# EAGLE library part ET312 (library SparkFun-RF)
ET312 GPS Receiver Proven layout and schematic for SiRF III ET312 GPS receiver. This footprint has been tweaked significantly to work with the ET312. This footprint has been fully qualified. Spark Fun Electronics SKU : GPS-08268.

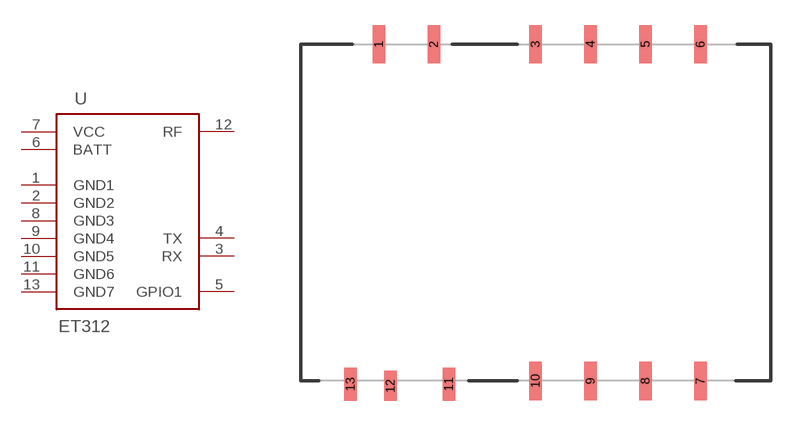
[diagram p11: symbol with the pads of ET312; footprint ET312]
Designator prefix -

## ET312SMD  [ET312]
1  GND1  pwr
2  GND2  pwr
3  RX  in
4  TX  out
5  GPIO1
6  BATT  pwr
7  VCC  pwr
8  GND3  pwr
9  GND4  pwr
10  GND5  pwr
11  GND6  pwr
12  RF
13  GND7  pwr

## Footprint ET312 (pad centres in mm)
smd 0.75 x 2.3: 1 -9.4,10.1; 2 -6.1,10.1; 3 0,10.1; 4 3.3,10.1; 5 6.6,10.1; 6 9.9,10.1; 7 9.9,-10.1; 8 6.6,-10.1; 9 3.3,-10.1; 10 0,-10.1
smd 0.75 x 2: 11 -5.2,-10.3; 13 -11.1,-10.3
smd 0.75 x 1.8: 12 -8.7,-10.4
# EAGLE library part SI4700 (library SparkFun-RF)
Silicon Labs FM Receiver 76-108 MHz FM band support with integrated VCO, automatic gain control, automatic frequency control and seek tuning.

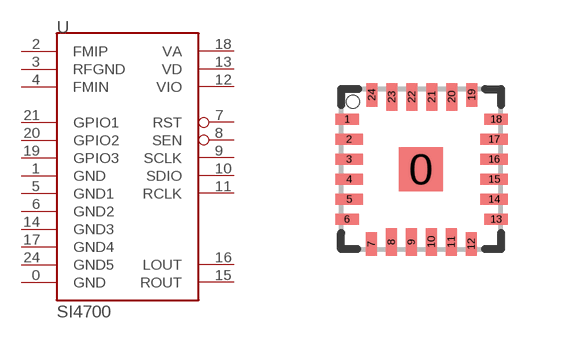
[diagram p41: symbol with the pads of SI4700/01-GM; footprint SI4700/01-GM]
Designator prefix -

## SI4700SMD  [SI4700/01-GM]
0  GND
1  GND
2  FMIP  in
3  RFGND
4  FMIN  in
5  GND1
6  GND2
7  RST
8  SEN
9  SCLK
10  SDIO
11  RCLK
12  VIO  pwr
13  VD  pwr
14  GND3
15  ROUT
16  LOUT
17  GND4
18  VA  pwr
19  GPIO3
20  GPIO2
21  GPIO1
24  GND5

## Footprint SI4700/01-GM (pad centres in mm)
smd 1.1 x 1.1: 0 0,0
smd 0.59 x 0.28: 1 -1.85,1.25; 6 -1.85,-1.25; 13 1.88,-1.25; 18 1.88,1.25
smd 0.69 x 0.28: 2 -1.8,0.75; 3 -1.8,0.25; 4 -1.8,-0.25; 5 -1.8,-0.75; 14 1.83,-0.75; 15 1.83,-0.25; 16 1.83,0.25; 17 1.83,0.75
smd 0.28 x 0.59: 7 -1.24,-1.87; 12 1.26,-1.87; 19 1.27,1.86; 24 -1.23,1.86
smd 0.28 x 0.69: 8 -0.74,-1.82; 9 -0.24,-1.82; 10 0.26,-1.82; 11 0.76,-1.82; 20 0.77,1.81; 21 0.27,1.81; 22 -0.23,1.81; 23 -0.73,1.81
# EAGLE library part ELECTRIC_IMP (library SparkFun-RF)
Electric Imp SD Socket This symbol matches the Electric Imp pinout to a 4UCONN SD MMC connector. The 4UCONN part number is 19646. See this part in action on the Electric Imp Breakout.

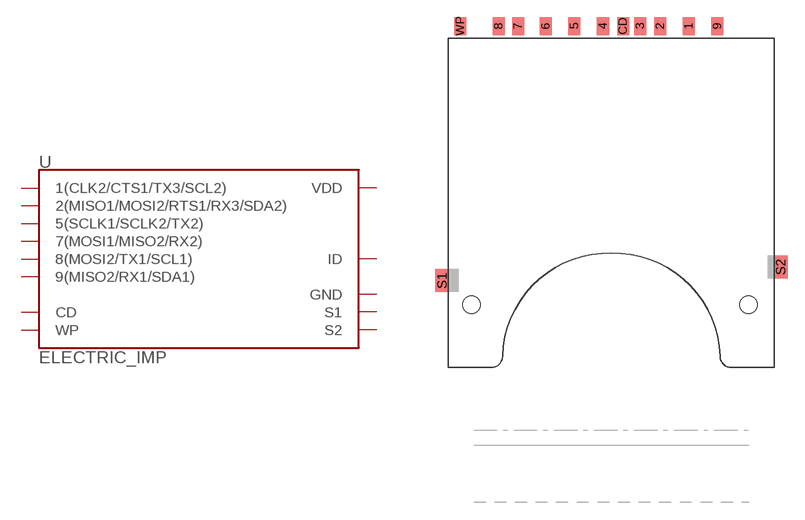
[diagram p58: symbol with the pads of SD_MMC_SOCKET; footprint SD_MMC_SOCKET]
Designator prefix U

## ELECTRIC_IMP  [SD_MMC_SOCKET]
1  1(CLK2/CTS1/TX3/SCL2)
2  2(MISO1/MOSI2/RTS1/RX3/SDA2)
3  GND
4  VDD
5  5(SCLK1/SCLK2/TX2)
6  ID
7  7(MOSI1/MISO2/RX2)
8  8(MOSI2/TX1/SCL1)
9  9(MISO2/RX1/SDA1)
CD  CD
S1  S1
S2  S2
WP  WP

## Footprint SD_MMC_SOCKET (pad centres in mm)
SD/Multi-Media Card Socket 4UCONN part # 19646
smd 1.05 x 1.56: 1 6.77,29.87; 2 4.27,29.87; 3 2.52,29.87; 4 -0.73,29.87; 5 -3.23,29.87; 6 -5.73,29.87; 7 -8.15,29.87; 8 -9.85,29.87; 9 9.27,29.87; CD 1.02,29.87; WP -13.2,29.87
smd 1.2 x 2: S1 -14.8,7.6; S2 14.8,8.8
hole 1.55 at 11.98,5.5
hole 1.55 at -12.22,5.5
